VERSION 5.7 ;
  NOWIREEXTENSIONATPIN ON ;
  DIVIDERCHAR "/" ;
  BUSBITCHARS "[]" ;
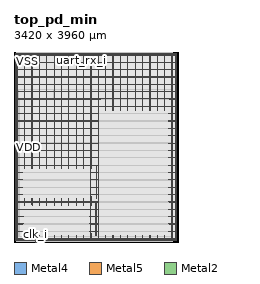
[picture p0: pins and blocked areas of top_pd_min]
MACRO top_pd_min
  CLASS BLOCK ;
  FOREIGN top_pd_min ;
  ORIGIN 0.000 0.000 ;
  SIZE 3420.000 BY 3960.000 ;
  PIN VDD
    DIRECTION INOUT ;
    USE POWER ;
    PORT
      LAYER Metal4 ;
        RECT 42.800 43.360 44.400 3915.840 ;
    END
    PORT
      LAYER Metal4 ;
        RECT 3375.520 43.360 3377.120 3915.840 ;
    END
    PORT
      LAYER Metal5 ;
        RECT 42.800 43.360 3377.120 44.960 ;
    END
    PORT
      LAYER Metal5 ;
        RECT 42.800 3914.240 3377.120 3915.840 ;
    END
    PORT
      LAYER Metal4 ;
        RECT 65.920 40.060 67.520 3919.140 ;
    END
    PORT
      LAYER Metal4 ;
        RECT 219.520 40.060 221.120 139.810 ;
    END
    PORT
      LAYER Metal4 ;
        RECT 219.520 771.220 221.120 909.810 ;
    END
    PORT
      LAYER Metal4 ;
        RECT 219.520 1541.220 221.120 3919.140 ;
    END
    PORT
      LAYER Metal4 ;
        RECT 373.120 40.060 374.720 139.810 ;
    END
    PORT
      LAYER Metal4 ;
        RECT 373.120 771.220 374.720 909.810 ;
    END
    PORT
      LAYER Metal4 ;
        RECT 373.120 1541.220 374.720 3919.140 ;
    END
    PORT
      LAYER Metal4 ;
        RECT 526.720 40.060 528.320 139.810 ;
    END
    PORT
      LAYER Metal4 ;
        RECT 526.720 771.220 528.320 909.810 ;
    END
    PORT
      LAYER Metal4 ;
        RECT 526.720 1541.220 528.320 3919.140 ;
    END
    PORT
      LAYER Metal4 ;
        RECT 680.320 40.060 681.920 139.810 ;
    END
    PORT
      LAYER Metal4 ;
        RECT 680.320 771.220 681.920 909.810 ;
    END
    PORT
      LAYER Metal4 ;
        RECT 680.320 1541.220 681.920 3919.140 ;
    END
    PORT
      LAYER Metal4 ;
        RECT 833.920 40.060 835.520 139.810 ;
    END
    PORT
      LAYER Metal4 ;
        RECT 833.920 771.220 835.520 909.810 ;
    END
    PORT
      LAYER Metal4 ;
        RECT 833.920 1541.220 835.520 3919.140 ;
    END
    PORT
      LAYER Metal4 ;
        RECT 987.520 40.060 989.120 139.810 ;
    END
    PORT
      LAYER Metal4 ;
        RECT 987.520 771.220 989.120 909.810 ;
    END
    PORT
      LAYER Metal4 ;
        RECT 987.520 1541.220 989.120 3919.140 ;
    END
    PORT
      LAYER Metal4 ;
        RECT 1141.120 40.060 1142.720 139.810 ;
    END
    PORT
      LAYER Metal4 ;
        RECT 1141.120 771.220 1142.720 909.810 ;
    END
    PORT
      LAYER Metal4 ;
        RECT 1141.120 1541.220 1142.720 3919.140 ;
    END
    PORT
      LAYER Metal4 ;
        RECT 1294.720 40.060 1296.320 139.810 ;
    END
    PORT
      LAYER Metal4 ;
        RECT 1294.720 771.220 1296.320 909.810 ;
    END
    PORT
      LAYER Metal4 ;
        RECT 1294.720 1541.220 1296.320 3919.140 ;
    END
    PORT
      LAYER Metal4 ;
        RECT 1448.320 40.060 1449.920 139.810 ;
    END
    PORT
      LAYER Metal4 ;
        RECT 1448.320 771.220 1449.920 909.810 ;
    END
    PORT
      LAYER Metal4 ;
        RECT 1448.320 1541.220 1449.920 3919.140 ;
    END
    PORT
      LAYER Metal4 ;
        RECT 1601.920 40.060 1603.520 3919.140 ;
    END
    PORT
      LAYER Metal4 ;
        RECT 1755.520 40.060 1757.120 3919.140 ;
    END
    PORT
      LAYER Metal4 ;
        RECT 1909.120 40.060 1910.720 139.810 ;
    END
    PORT
      LAYER Metal4 ;
        RECT 1909.120 2734.020 1910.720 3919.140 ;
    END
    PORT
      LAYER Metal4 ;
        RECT 2062.720 40.060 2064.320 139.810 ;
    END
    PORT
      LAYER Metal4 ;
        RECT 2062.720 2734.020 2064.320 3919.140 ;
    END
    PORT
      LAYER Metal4 ;
        RECT 2216.320 40.060 2217.920 139.810 ;
    END
    PORT
      LAYER Metal4 ;
        RECT 2216.320 2734.020 2217.920 3919.140 ;
    END
    PORT
      LAYER Metal4 ;
        RECT 2369.920 40.060 2371.520 139.810 ;
    END
    PORT
      LAYER Metal4 ;
        RECT 2369.920 2734.020 2371.520 3919.140 ;
    END
    PORT
      LAYER Metal4 ;
        RECT 2523.520 40.060 2525.120 139.810 ;
    END
    PORT
      LAYER Metal4 ;
        RECT 2523.520 2734.020 2525.120 3919.140 ;
    END
    PORT
      LAYER Metal4 ;
        RECT 2677.120 40.060 2678.720 139.810 ;
    END
    PORT
      LAYER Metal4 ;
        RECT 2677.120 2734.020 2678.720 3919.140 ;
    END
    PORT
      LAYER Metal4 ;
        RECT 2830.720 40.060 2832.320 139.810 ;
    END
    PORT
      LAYER Metal4 ;
        RECT 2830.720 2734.020 2832.320 3919.140 ;
    END
    PORT
      LAYER Metal4 ;
        RECT 2984.320 40.060 2985.920 139.810 ;
    END
    PORT
      LAYER Metal4 ;
        RECT 2984.320 2734.020 2985.920 3919.140 ;
    END
    PORT
      LAYER Metal4 ;
        RECT 3137.920 40.060 3139.520 139.810 ;
    END
    PORT
      LAYER Metal4 ;
        RECT 3137.920 2734.020 3139.520 3919.140 ;
    END
    PORT
      LAYER Metal4 ;
        RECT 3291.520 40.060 3293.120 3919.140 ;
    END
    PORT
      LAYER Metal5 ;
        RECT 39.500 66.810 3380.420 68.410 ;
    END
    PORT
      LAYER Metal5 ;
        RECT 39.500 219.990 178.580 221.590 ;
    END
    PORT
      LAYER Metal5 ;
        RECT 39.500 373.170 178.580 374.770 ;
    END
    PORT
      LAYER Metal5 ;
        RECT 39.500 526.350 178.580 527.950 ;
    END
    PORT
      LAYER Metal5 ;
        RECT 39.500 679.530 178.580 681.130 ;
    END
    PORT
      LAYER Metal5 ;
        RECT 39.500 832.710 1770.800 834.310 ;
    END
    PORT
      LAYER Metal5 ;
        RECT 39.500 985.890 178.580 987.490 ;
    END
    PORT
      LAYER Metal5 ;
        RECT 39.500 1139.070 178.580 1140.670 ;
    END
    PORT
      LAYER Metal5 ;
        RECT 39.500 1292.250 178.580 1293.850 ;
    END
    PORT
      LAYER Metal5 ;
        RECT 39.500 1445.430 178.580 1447.030 ;
    END
    PORT
      LAYER Metal5 ;
        RECT 39.500 1598.610 1770.800 1600.210 ;
    END
    PORT
      LAYER Metal5 ;
        RECT 39.500 1751.790 1770.800 1753.390 ;
    END
    PORT
      LAYER Metal5 ;
        RECT 39.500 1904.970 1770.800 1906.570 ;
    END
    PORT
      LAYER Metal5 ;
        RECT 39.500 2058.150 1770.800 2059.750 ;
    END
    PORT
      LAYER Metal5 ;
        RECT 39.500 2211.330 1770.800 2212.930 ;
    END
    PORT
      LAYER Metal5 ;
        RECT 39.500 2364.510 1770.800 2366.110 ;
    END
    PORT
      LAYER Metal5 ;
        RECT 39.500 2517.690 1770.800 2519.290 ;
    END
    PORT
      LAYER Metal5 ;
        RECT 39.500 2670.870 1770.800 2672.470 ;
    END
    PORT
      LAYER Metal5 ;
        RECT 39.500 2824.050 1798.580 2825.650 ;
    END
    PORT
      LAYER Metal5 ;
        RECT 39.500 2977.230 1798.580 2978.830 ;
    END
    PORT
      LAYER Metal5 ;
        RECT 39.500 3130.410 3380.420 3132.010 ;
    END
    PORT
      LAYER Metal5 ;
        RECT 39.500 3283.590 3380.420 3285.190 ;
    END
    PORT
      LAYER Metal5 ;
        RECT 39.500 3436.770 3380.420 3438.370 ;
    END
    PORT
      LAYER Metal5 ;
        RECT 39.500 3589.950 3380.420 3591.550 ;
    END
    PORT
      LAYER Metal5 ;
        RECT 39.500 3743.130 3380.420 3744.730 ;
    END
    PORT
      LAYER Metal5 ;
        RECT 39.500 3896.310 3380.420 3897.910 ;
    END
    PORT
      LAYER Metal5 ;
        RECT 1621.660 219.990 1770.800 221.590 ;
    END
    PORT
      LAYER Metal5 ;
        RECT 1621.660 373.170 1770.800 374.770 ;
    END
    PORT
      LAYER Metal5 ;
        RECT 1621.660 526.350 1770.800 527.950 ;
    END
    PORT
      LAYER Metal5 ;
        RECT 1621.660 679.530 1770.800 681.130 ;
    END
    PORT
      LAYER Metal5 ;
        RECT 1621.660 985.890 1770.800 987.490 ;
    END
    PORT
      LAYER Metal5 ;
        RECT 1621.660 1139.070 1770.800 1140.670 ;
    END
    PORT
      LAYER Metal5 ;
        RECT 1621.660 1292.250 1770.800 1293.850 ;
    END
    PORT
      LAYER Metal5 ;
        RECT 1621.660 1445.430 1770.800 1447.030 ;
    END
    PORT
      LAYER Metal5 ;
        RECT 3241.660 219.990 3380.420 221.590 ;
    END
    PORT
      LAYER Metal5 ;
        RECT 3241.660 373.170 3380.420 374.770 ;
    END
    PORT
      LAYER Metal5 ;
        RECT 3241.660 526.350 3380.420 527.950 ;
    END
    PORT
      LAYER Metal5 ;
        RECT 3241.660 679.530 3380.420 681.130 ;
    END
    PORT
      LAYER Metal5 ;
        RECT 3241.660 832.710 3380.420 834.310 ;
    END
    PORT
      LAYER Metal5 ;
        RECT 3241.660 985.890 3380.420 987.490 ;
    END
    PORT
      LAYER Metal5 ;
        RECT 3241.660 1139.070 3380.420 1140.670 ;
    END
    PORT
      LAYER Metal5 ;
        RECT 3241.660 1292.250 3380.420 1293.850 ;
    END
    PORT
      LAYER Metal5 ;
        RECT 3241.660 1445.430 3380.420 1447.030 ;
    END
    PORT
      LAYER Metal5 ;
        RECT 3241.660 1598.610 3380.420 1600.210 ;
    END
    PORT
      LAYER Metal5 ;
        RECT 3241.660 1751.790 3380.420 1753.390 ;
    END
    PORT
      LAYER Metal5 ;
        RECT 3241.660 1904.970 3380.420 1906.570 ;
    END
    PORT
      LAYER Metal5 ;
        RECT 3241.660 2058.150 3380.420 2059.750 ;
    END
    PORT
      LAYER Metal5 ;
        RECT 3241.660 2211.330 3380.420 2212.930 ;
    END
    PORT
      LAYER Metal5 ;
        RECT 3241.660 2364.510 3380.420 2366.110 ;
    END
    PORT
      LAYER Metal5 ;
        RECT 3241.660 2517.690 3380.420 2519.290 ;
    END
    PORT
      LAYER Metal5 ;
        RECT 3241.660 2670.870 3380.420 2672.470 ;
    END
    PORT
      LAYER Metal5 ;
        RECT 3241.660 2824.050 3380.420 2825.650 ;
    END
    PORT
      LAYER Metal5 ;
        RECT 3241.660 2977.230 3380.420 2978.830 ;
    END
  END VDD
  PIN VSS
    DIRECTION INOUT ;
    USE GROUND ;
    PORT
      LAYER Metal4 ;
        RECT 39.500 40.060 41.100 3919.140 ;
    END
    PORT
      LAYER Metal4 ;
        RECT 3378.820 40.060 3380.420 3919.140 ;
    END
    PORT
      LAYER Metal5 ;
        RECT 39.500 40.060 3380.420 41.660 ;
    END
    PORT
      LAYER Metal5 ;
        RECT 39.500 3917.540 3380.420 3919.140 ;
    END
    PORT
      LAYER Metal4 ;
        RECT 69.220 40.060 70.820 3919.140 ;
    END
    PORT
      LAYER Metal4 ;
        RECT 222.820 40.060 224.420 139.810 ;
    END
    PORT
      LAYER Metal4 ;
        RECT 222.820 758.830 224.420 909.810 ;
    END
    PORT
      LAYER Metal4 ;
        RECT 222.820 1528.830 224.420 3919.140 ;
    END
    PORT
      LAYER Metal4 ;
        RECT 376.420 40.060 378.020 139.810 ;
    END
    PORT
      LAYER Metal4 ;
        RECT 376.420 758.830 378.020 909.810 ;
    END
    PORT
      LAYER Metal4 ;
        RECT 376.420 1528.830 378.020 3919.140 ;
    END
    PORT
      LAYER Metal4 ;
        RECT 530.020 40.060 531.620 139.810 ;
    END
    PORT
      LAYER Metal4 ;
        RECT 530.020 758.830 531.620 909.810 ;
    END
    PORT
      LAYER Metal4 ;
        RECT 530.020 1528.830 531.620 3919.140 ;
    END
    PORT
      LAYER Metal4 ;
        RECT 683.620 40.060 685.220 139.810 ;
    END
    PORT
      LAYER Metal4 ;
        RECT 683.620 758.830 685.220 909.810 ;
    END
    PORT
      LAYER Metal4 ;
        RECT 683.620 1528.830 685.220 3919.140 ;
    END
    PORT
      LAYER Metal4 ;
        RECT 837.220 40.060 838.820 139.810 ;
    END
    PORT
      LAYER Metal4 ;
        RECT 837.220 758.830 838.820 909.810 ;
    END
    PORT
      LAYER Metal4 ;
        RECT 837.220 1528.830 838.820 3919.140 ;
    END
    PORT
      LAYER Metal4 ;
        RECT 990.820 40.060 992.420 139.810 ;
    END
    PORT
      LAYER Metal4 ;
        RECT 990.820 758.830 992.420 909.810 ;
    END
    PORT
      LAYER Metal4 ;
        RECT 990.820 1528.830 992.420 3919.140 ;
    END
    PORT
      LAYER Metal4 ;
        RECT 1144.420 40.060 1146.020 139.810 ;
    END
    PORT
      LAYER Metal4 ;
        RECT 1144.420 758.830 1146.020 909.810 ;
    END
    PORT
      LAYER Metal4 ;
        RECT 1144.420 1528.830 1146.020 3919.140 ;
    END
    PORT
      LAYER Metal4 ;
        RECT 1298.020 40.060 1299.620 139.810 ;
    END
    PORT
      LAYER Metal4 ;
        RECT 1298.020 758.830 1299.620 909.810 ;
    END
    PORT
      LAYER Metal4 ;
        RECT 1298.020 1528.830 1299.620 3919.140 ;
    END
    PORT
      LAYER Metal4 ;
        RECT 1451.620 40.060 1453.220 139.810 ;
    END
    PORT
      LAYER Metal4 ;
        RECT 1451.620 758.830 1453.220 909.810 ;
    END
    PORT
      LAYER Metal4 ;
        RECT 1451.620 1528.830 1453.220 3919.140 ;
    END
    PORT
      LAYER Metal4 ;
        RECT 1605.220 40.060 1606.820 182.800 ;
    END
    PORT
      LAYER Metal4 ;
        RECT 1605.220 767.920 1606.820 952.800 ;
    END
    PORT
      LAYER Metal4 ;
        RECT 1605.220 1537.920 1606.820 3919.140 ;
    END
    PORT
      LAYER Metal4 ;
        RECT 1758.820 40.060 1760.420 139.810 ;
    END
    PORT
      LAYER Metal4 ;
        RECT 1758.820 2734.020 1760.420 3919.140 ;
    END
    PORT
      LAYER Metal4 ;
        RECT 1912.420 40.060 1914.020 139.810 ;
    END
    PORT
      LAYER Metal4 ;
        RECT 1912.420 2734.020 1914.020 3919.140 ;
    END
    PORT
      LAYER Metal4 ;
        RECT 2066.020 40.060 2067.620 139.810 ;
    END
    PORT
      LAYER Metal4 ;
        RECT 2066.020 2734.020 2067.620 3919.140 ;
    END
    PORT
      LAYER Metal4 ;
        RECT 2219.620 40.060 2221.220 139.810 ;
    END
    PORT
      LAYER Metal4 ;
        RECT 2219.620 2734.020 2221.220 3919.140 ;
    END
    PORT
      LAYER Metal4 ;
        RECT 2373.220 40.060 2374.820 139.810 ;
    END
    PORT
      LAYER Metal4 ;
        RECT 2373.220 2734.020 2374.820 3919.140 ;
    END
    PORT
      LAYER Metal4 ;
        RECT 2526.820 40.060 2528.420 139.810 ;
    END
    PORT
      LAYER Metal4 ;
        RECT 2526.820 2734.020 2528.420 3919.140 ;
    END
    PORT
      LAYER Metal4 ;
        RECT 2680.420 40.060 2682.020 139.810 ;
    END
    PORT
      LAYER Metal4 ;
        RECT 2680.420 2734.020 2682.020 3919.140 ;
    END
    PORT
      LAYER Metal4 ;
        RECT 2834.020 40.060 2835.620 139.810 ;
    END
    PORT
      LAYER Metal4 ;
        RECT 2834.020 2734.020 2835.620 3919.140 ;
    END
    PORT
      LAYER Metal4 ;
        RECT 2987.620 40.060 2989.220 139.810 ;
    END
    PORT
      LAYER Metal4 ;
        RECT 2987.620 2734.020 2989.220 3919.140 ;
    END
    PORT
      LAYER Metal4 ;
        RECT 3141.220 40.060 3142.820 139.810 ;
    END
    PORT
      LAYER Metal4 ;
        RECT 3141.220 2734.020 3142.820 3919.140 ;
    END
    PORT
      LAYER Metal4 ;
        RECT 3294.820 40.060 3296.420 3919.140 ;
    END
    PORT
      LAYER Metal5 ;
        RECT 39.500 70.110 3380.420 71.710 ;
    END
    PORT
      LAYER Metal5 ;
        RECT 39.500 223.290 189.440 224.890 ;
    END
    PORT
      LAYER Metal5 ;
        RECT 39.500 376.470 189.440 378.070 ;
    END
    PORT
      LAYER Metal5 ;
        RECT 39.500 529.650 189.440 531.250 ;
    END
    PORT
      LAYER Metal5 ;
        RECT 39.500 682.830 1770.800 684.430 ;
    END
    PORT
      LAYER Metal5 ;
        RECT 39.500 836.010 1770.800 837.610 ;
    END
    PORT
      LAYER Metal5 ;
        RECT 39.500 989.190 178.580 990.790 ;
    END
    PORT
      LAYER Metal5 ;
        RECT 39.500 1142.370 178.580 1143.970 ;
    END
    PORT
      LAYER Metal5 ;
        RECT 39.500 1295.550 178.580 1297.150 ;
    END
    PORT
      LAYER Metal5 ;
        RECT 39.500 1448.730 178.580 1450.330 ;
    END
    PORT
      LAYER Metal5 ;
        RECT 39.500 1601.910 1770.800 1603.510 ;
    END
    PORT
      LAYER Metal5 ;
        RECT 39.500 1755.090 1770.800 1756.690 ;
    END
    PORT
      LAYER Metal5 ;
        RECT 39.500 1908.270 1770.800 1909.870 ;
    END
    PORT
      LAYER Metal5 ;
        RECT 39.500 2061.450 1770.800 2063.050 ;
    END
    PORT
      LAYER Metal5 ;
        RECT 39.500 2214.630 1770.800 2216.230 ;
    END
    PORT
      LAYER Metal5 ;
        RECT 39.500 2367.810 1770.800 2369.410 ;
    END
    PORT
      LAYER Metal5 ;
        RECT 39.500 2520.990 1770.800 2522.590 ;
    END
    PORT
      LAYER Metal5 ;
        RECT 39.500 2674.170 1770.800 2675.770 ;
    END
    PORT
      LAYER Metal5 ;
        RECT 39.500 2827.350 3380.420 2828.950 ;
    END
    PORT
      LAYER Metal5 ;
        RECT 39.500 2980.530 3380.420 2982.130 ;
    END
    PORT
      LAYER Metal5 ;
        RECT 39.500 3133.710 3380.420 3135.310 ;
    END
    PORT
      LAYER Metal5 ;
        RECT 39.500 3286.890 3380.420 3288.490 ;
    END
    PORT
      LAYER Metal5 ;
        RECT 39.500 3440.070 3380.420 3441.670 ;
    END
    PORT
      LAYER Metal5 ;
        RECT 39.500 3593.250 3380.420 3594.850 ;
    END
    PORT
      LAYER Metal5 ;
        RECT 39.500 3746.430 3380.420 3748.030 ;
    END
    PORT
      LAYER Metal5 ;
        RECT 39.500 3899.610 3380.420 3901.210 ;
    END
    PORT
      LAYER Metal5 ;
        RECT 1579.440 223.290 1770.800 224.890 ;
    END
    PORT
      LAYER Metal5 ;
        RECT 1579.440 376.470 1770.800 378.070 ;
    END
    PORT
      LAYER Metal5 ;
        RECT 1579.440 529.650 1770.800 531.250 ;
    END
    PORT
      LAYER Metal5 ;
        RECT 1621.660 989.190 1770.800 990.790 ;
    END
    PORT
      LAYER Metal5 ;
        RECT 1621.660 1142.370 1770.800 1143.970 ;
    END
    PORT
      LAYER Metal5 ;
        RECT 1621.660 1295.550 1770.800 1297.150 ;
    END
    PORT
      LAYER Metal5 ;
        RECT 1621.660 1448.730 1770.800 1450.330 ;
    END
    PORT
      LAYER Metal5 ;
        RECT 3227.440 223.290 3380.420 224.890 ;
    END
    PORT
      LAYER Metal5 ;
        RECT 3227.440 376.470 3380.420 378.070 ;
    END
    PORT
      LAYER Metal5 ;
        RECT 3227.440 529.650 3380.420 531.250 ;
    END
    PORT
      LAYER Metal5 ;
        RECT 3227.440 682.830 3380.420 684.430 ;
    END
    PORT
      LAYER Metal5 ;
        RECT 3227.440 836.010 3380.420 837.610 ;
    END
    PORT
      LAYER Metal5 ;
        RECT 3227.440 989.190 3380.420 990.790 ;
    END
    PORT
      LAYER Metal5 ;
        RECT 3227.440 1142.370 3380.420 1143.970 ;
    END
    PORT
      LAYER Metal5 ;
        RECT 3227.440 1295.550 3380.420 1297.150 ;
    END
    PORT
      LAYER Metal5 ;
        RECT 3227.440 1448.730 3380.420 1450.330 ;
    END
    PORT
      LAYER Metal5 ;
        RECT 3227.440 1601.910 3380.420 1603.510 ;
    END
    PORT
      LAYER Metal5 ;
        RECT 3227.440 1755.090 3380.420 1756.690 ;
    END
    PORT
      LAYER Metal5 ;
        RECT 3227.440 1908.270 3380.420 1909.870 ;
    END
    PORT
      LAYER Metal5 ;
        RECT 3227.440 2061.450 3380.420 2063.050 ;
    END
    PORT
      LAYER Metal5 ;
        RECT 3227.440 2214.630 3380.420 2216.230 ;
    END
    PORT
      LAYER Metal5 ;
        RECT 3227.440 2367.810 3380.420 2369.410 ;
    END
    PORT
      LAYER Metal5 ;
        RECT 3227.440 2520.990 3380.420 2522.590 ;
    END
    PORT
      LAYER Metal5 ;
        RECT 3227.440 2674.170 3380.420 2675.770 ;
    END
    PORT
      LAYER Metal4 ;
        RECT 1708.600 136.900 1710.200 811.740 ;
    END
    PORT
      LAYER Metal4 ;
        RECT 1709.160 905.220 1710.760 1587.900 ;
    END
  END VSS
  PIN clk_i
    DIRECTION INPUT ;
    USE SIGNAL ;
    ANTENNAGATEAREA 9.476000 ;
    PORT
      LAYER Metal2 ;
        RECT 449.120 0.000 449.680 0.560 ;
    END
  END clk_i
  PIN rst_ni
    DIRECTION INPUT ;
    USE SIGNAL ;
    ANTENNAGATEAREA 0.396000 ;
    PORT
      LAYER Metal2 ;
        RECT 450.240 0.000 450.800 0.560 ;
    END
  END rst_ni
  PIN uart_rx_i
    DIRECTION INPUT ;
    USE SIGNAL ;
    ANTENNAGATEAREA 0.726000 ;
    PORT
      LAYER Metal2 ;
        RECT 1413.440 3959.440 1414.000 3960.000 ;
    END
  END uart_rx_i
  PIN uart_tx_en_o
    DIRECTION OUTPUT ;
    USE SIGNAL ;
    ANTENNADIFFAREA 0.536800 ;
    PORT
      LAYER Metal2 ;
        RECT 324.800 3959.440 325.360 3960.000 ;
    END
  END uart_tx_en_o
  PIN uart_tx_o
    DIRECTION OUTPUT ;
    USE SIGNAL ;
    ANTENNADIFFAREA 0.897600 ;
    PORT
      LAYER Metal2 ;
        RECT 1412.320 3959.440 1412.880 3960.000 ;
    END
  END uart_tx_o
  OBS
      LAYER Nwell ;
        RECT 49.970 50.530 3369.950 3908.670 ;
      LAYER Metal1 ;
        RECT 50.400 50.660 3369.520 3908.540 ;
      LAYER Metal2 ;
        RECT 52.780 3959.140 324.500 3959.440 ;
        RECT 325.660 3959.140 1412.020 3959.440 ;
        RECT 1414.300 3959.140 3296.280 3959.440 ;
        RECT 52.780 0.860 3296.280 3959.140 ;
        RECT 52.780 0.090 448.820 0.860 ;
        RECT 451.100 0.090 3296.280 0.860 ;
      LAYER Metal3 ;
        RECT 52.730 0.140 3296.330 3914.260 ;
      LAYER Metal4 ;
        RECT 84.140 1540.920 219.220 3183.510 ;
        RECT 221.420 1540.920 222.520 3183.510 ;
        RECT 84.140 1528.530 222.520 1540.920 ;
        RECT 224.720 1540.920 372.820 3183.510 ;
        RECT 375.020 1540.920 376.120 3183.510 ;
        RECT 224.720 1528.530 376.120 1540.920 ;
        RECT 378.320 1540.920 526.420 3183.510 ;
        RECT 528.620 1540.920 529.720 3183.510 ;
        RECT 378.320 1528.530 529.720 1540.920 ;
        RECT 531.920 1540.920 680.020 3183.510 ;
        RECT 682.220 1540.920 683.320 3183.510 ;
        RECT 531.920 1528.530 683.320 1540.920 ;
        RECT 685.520 1540.920 833.620 3183.510 ;
        RECT 835.820 1540.920 836.920 3183.510 ;
        RECT 685.520 1528.530 836.920 1540.920 ;
        RECT 839.120 1540.920 987.220 3183.510 ;
        RECT 989.420 1540.920 990.520 3183.510 ;
        RECT 839.120 1528.530 990.520 1540.920 ;
        RECT 992.720 1540.920 1140.820 3183.510 ;
        RECT 1143.020 1540.920 1144.120 3183.510 ;
        RECT 992.720 1528.530 1144.120 1540.920 ;
        RECT 1146.320 1540.920 1294.420 3183.510 ;
        RECT 1296.620 1540.920 1297.720 3183.510 ;
        RECT 1146.320 1528.530 1297.720 1540.920 ;
        RECT 1299.920 1540.920 1448.020 3183.510 ;
        RECT 1450.220 1540.920 1451.320 3183.510 ;
        RECT 1299.920 1528.530 1451.320 1540.920 ;
        RECT 1453.520 1528.530 1601.620 3183.510 ;
        RECT 84.140 910.110 1601.620 1528.530 ;
        RECT 84.140 770.920 219.220 910.110 ;
        RECT 221.420 770.920 222.520 910.110 ;
        RECT 84.140 758.530 222.520 770.920 ;
        RECT 224.720 770.920 372.820 910.110 ;
        RECT 375.020 770.920 376.120 910.110 ;
        RECT 224.720 758.530 376.120 770.920 ;
        RECT 378.320 770.920 526.420 910.110 ;
        RECT 528.620 770.920 529.720 910.110 ;
        RECT 378.320 758.530 529.720 770.920 ;
        RECT 531.920 770.920 680.020 910.110 ;
        RECT 682.220 770.920 683.320 910.110 ;
        RECT 531.920 758.530 683.320 770.920 ;
        RECT 685.520 770.920 833.620 910.110 ;
        RECT 835.820 770.920 836.920 910.110 ;
        RECT 685.520 758.530 836.920 770.920 ;
        RECT 839.120 770.920 987.220 910.110 ;
        RECT 989.420 770.920 990.520 910.110 ;
        RECT 839.120 758.530 990.520 770.920 ;
        RECT 992.720 770.920 1140.820 910.110 ;
        RECT 1143.020 770.920 1144.120 910.110 ;
        RECT 992.720 758.530 1144.120 770.920 ;
        RECT 1146.320 770.920 1294.420 910.110 ;
        RECT 1296.620 770.920 1297.720 910.110 ;
        RECT 1146.320 758.530 1297.720 770.920 ;
        RECT 1299.920 770.920 1448.020 910.110 ;
        RECT 1450.220 770.920 1451.320 910.110 ;
        RECT 1299.920 758.530 1451.320 770.920 ;
        RECT 1453.520 758.530 1601.620 910.110 ;
        RECT 84.140 140.110 1601.620 758.530 ;
        RECT 84.140 114.330 219.220 140.110 ;
        RECT 221.420 114.330 222.520 140.110 ;
        RECT 224.720 114.330 372.820 140.110 ;
        RECT 375.020 114.330 376.120 140.110 ;
        RECT 378.320 114.330 526.420 140.110 ;
        RECT 528.620 114.330 529.720 140.110 ;
        RECT 531.920 114.330 680.020 140.110 ;
        RECT 682.220 114.330 683.320 140.110 ;
        RECT 685.520 114.330 833.620 140.110 ;
        RECT 835.820 114.330 836.920 140.110 ;
        RECT 839.120 114.330 987.220 140.110 ;
        RECT 989.420 114.330 990.520 140.110 ;
        RECT 992.720 114.330 1140.820 140.110 ;
        RECT 1143.020 114.330 1144.120 140.110 ;
        RECT 1146.320 114.330 1294.420 140.110 ;
        RECT 1296.620 114.330 1297.720 140.110 ;
        RECT 1299.920 114.330 1448.020 140.110 ;
        RECT 1450.220 114.330 1451.320 140.110 ;
        RECT 1453.520 114.330 1601.620 140.110 ;
        RECT 1603.820 1537.620 1604.920 3183.510 ;
        RECT 1607.120 1588.200 1755.220 3183.510 ;
        RECT 1607.120 1537.620 1708.860 1588.200 ;
        RECT 1603.820 953.100 1708.860 1537.620 ;
        RECT 1603.820 767.620 1604.920 953.100 ;
        RECT 1607.120 904.920 1708.860 953.100 ;
        RECT 1711.060 904.920 1755.220 1588.200 ;
        RECT 1607.120 812.040 1755.220 904.920 ;
        RECT 1607.120 767.620 1708.300 812.040 ;
        RECT 1603.820 183.100 1708.300 767.620 ;
        RECT 1603.820 114.330 1604.920 183.100 ;
        RECT 1607.120 136.600 1708.300 183.100 ;
        RECT 1710.500 136.600 1755.220 812.040 ;
        RECT 1607.120 114.330 1755.220 136.600 ;
        RECT 1757.420 2733.720 1758.520 3183.510 ;
        RECT 1760.720 2733.720 1908.820 3183.510 ;
        RECT 1911.020 2733.720 1912.120 3183.510 ;
        RECT 1914.320 2733.720 2062.420 3183.510 ;
        RECT 2064.620 2733.720 2065.720 3183.510 ;
        RECT 2067.920 2733.720 2216.020 3183.510 ;
        RECT 2218.220 2733.720 2219.320 3183.510 ;
        RECT 2221.520 2733.720 2369.620 3183.510 ;
        RECT 2371.820 2733.720 2372.920 3183.510 ;
        RECT 2375.120 2733.720 2523.220 3183.510 ;
        RECT 2525.420 2733.720 2526.520 3183.510 ;
        RECT 2528.720 2733.720 2676.820 3183.510 ;
        RECT 2679.020 2733.720 2680.120 3183.510 ;
        RECT 2682.320 2733.720 2830.420 3183.510 ;
        RECT 2832.620 2733.720 2833.720 3183.510 ;
        RECT 2835.920 2733.720 2984.020 3183.510 ;
        RECT 2986.220 2733.720 2987.320 3183.510 ;
        RECT 2989.520 2733.720 3137.620 3183.510 ;
        RECT 3139.820 2733.720 3140.920 3183.510 ;
        RECT 3143.120 2733.720 3289.860 3183.510 ;
        RECT 1757.420 140.110 3289.860 2733.720 ;
        RECT 1757.420 114.330 1758.520 140.110 ;
        RECT 1760.720 114.330 1908.820 140.110 ;
        RECT 1911.020 114.330 1912.120 140.110 ;
        RECT 1914.320 114.330 2062.420 140.110 ;
        RECT 2064.620 114.330 2065.720 140.110 ;
        RECT 2067.920 114.330 2216.020 140.110 ;
        RECT 2218.220 114.330 2219.320 140.110 ;
        RECT 2221.520 114.330 2369.620 140.110 ;
        RECT 2371.820 114.330 2372.920 140.110 ;
        RECT 2375.120 114.330 2523.220 140.110 ;
        RECT 2525.420 114.330 2526.520 140.110 ;
        RECT 2528.720 114.330 2676.820 140.110 ;
        RECT 2679.020 114.330 2680.120 140.110 ;
        RECT 2682.320 114.330 2830.420 140.110 ;
        RECT 2832.620 114.330 2833.720 140.110 ;
        RECT 2835.920 114.330 2984.020 140.110 ;
        RECT 2986.220 114.330 2987.320 140.110 ;
        RECT 2989.520 114.330 3137.620 140.110 ;
        RECT 3139.820 114.330 3140.920 140.110 ;
        RECT 3143.120 114.330 3289.860 140.110 ;
      LAYER Metal5 ;
        RECT 117.100 2982.730 3289.940 2998.980 ;
        RECT 117.100 2979.430 3289.940 2979.930 ;
        RECT 1799.180 2976.630 3241.060 2979.430 ;
        RECT 117.100 2829.550 3289.940 2976.630 ;
        RECT 117.100 2826.250 3289.940 2826.750 ;
        RECT 1799.180 2823.450 3241.060 2826.250 ;
        RECT 117.100 2676.370 3289.940 2823.450 ;
        RECT 1771.400 2673.570 3226.840 2676.370 ;
        RECT 117.100 2673.070 3289.940 2673.570 ;
        RECT 1771.400 2670.270 3241.060 2673.070 ;
        RECT 117.100 2523.190 3289.940 2670.270 ;
        RECT 1771.400 2520.390 3226.840 2523.190 ;
        RECT 117.100 2519.890 3289.940 2520.390 ;
        RECT 1771.400 2517.090 3241.060 2519.890 ;
        RECT 117.100 2370.010 3289.940 2517.090 ;
        RECT 1771.400 2367.210 3226.840 2370.010 ;
        RECT 117.100 2366.710 3289.940 2367.210 ;
        RECT 1771.400 2363.910 3241.060 2366.710 ;
        RECT 117.100 2216.830 3289.940 2363.910 ;
        RECT 1771.400 2214.030 3226.840 2216.830 ;
        RECT 117.100 2213.530 3289.940 2214.030 ;
        RECT 1771.400 2210.730 3241.060 2213.530 ;
        RECT 117.100 2063.650 3289.940 2210.730 ;
        RECT 1771.400 2060.850 3226.840 2063.650 ;
        RECT 117.100 2060.350 3289.940 2060.850 ;
        RECT 1771.400 2057.550 3241.060 2060.350 ;
        RECT 117.100 1910.470 3289.940 2057.550 ;
        RECT 1771.400 1907.670 3226.840 1910.470 ;
        RECT 117.100 1907.170 3289.940 1907.670 ;
        RECT 1771.400 1904.370 3241.060 1907.170 ;
        RECT 117.100 1757.290 3289.940 1904.370 ;
        RECT 1771.400 1754.490 3226.840 1757.290 ;
        RECT 117.100 1753.990 3289.940 1754.490 ;
        RECT 1771.400 1751.190 3241.060 1753.990 ;
        RECT 117.100 1604.110 3289.940 1751.190 ;
        RECT 1771.400 1601.310 3226.840 1604.110 ;
        RECT 117.100 1600.810 3289.940 1601.310 ;
        RECT 1771.400 1598.010 3241.060 1600.810 ;
        RECT 117.100 1450.930 3289.940 1598.010 ;
        RECT 179.180 1448.130 1621.060 1450.930 ;
        RECT 1771.400 1448.130 3226.840 1450.930 ;
        RECT 117.100 1447.630 3289.940 1448.130 ;
        RECT 179.180 1444.830 1621.060 1447.630 ;
        RECT 1771.400 1444.830 3241.060 1447.630 ;
        RECT 117.100 1297.750 3289.940 1444.830 ;
        RECT 179.180 1294.950 1621.060 1297.750 ;
        RECT 1771.400 1294.950 3226.840 1297.750 ;
        RECT 117.100 1294.450 3289.940 1294.950 ;
        RECT 179.180 1291.650 1621.060 1294.450 ;
        RECT 1771.400 1291.650 3241.060 1294.450 ;
        RECT 117.100 1144.570 3289.940 1291.650 ;
        RECT 179.180 1141.770 1621.060 1144.570 ;
        RECT 1771.400 1141.770 3226.840 1144.570 ;
        RECT 117.100 1141.270 3289.940 1141.770 ;
        RECT 179.180 1138.470 1621.060 1141.270 ;
        RECT 1771.400 1138.470 3241.060 1141.270 ;
        RECT 117.100 991.390 3289.940 1138.470 ;
        RECT 179.180 988.590 1621.060 991.390 ;
        RECT 1771.400 988.590 3226.840 991.390 ;
        RECT 117.100 988.090 3289.940 988.590 ;
        RECT 179.180 985.290 1621.060 988.090 ;
        RECT 1771.400 985.290 3241.060 988.090 ;
        RECT 117.100 838.210 3289.940 985.290 ;
        RECT 1771.400 835.410 3226.840 838.210 ;
        RECT 117.100 834.910 3289.940 835.410 ;
        RECT 1771.400 832.110 3241.060 834.910 ;
        RECT 117.100 685.030 3289.940 832.110 ;
        RECT 1771.400 682.230 3226.840 685.030 ;
        RECT 117.100 681.730 3289.940 682.230 ;
        RECT 179.180 678.930 1621.060 681.730 ;
        RECT 1771.400 678.930 3241.060 681.730 ;
        RECT 117.100 531.850 3289.940 678.930 ;
        RECT 190.040 529.050 1578.840 531.850 ;
        RECT 1771.400 529.050 3226.840 531.850 ;
        RECT 117.100 528.550 3289.940 529.050 ;
        RECT 179.180 525.750 1621.060 528.550 ;
        RECT 1771.400 525.750 3241.060 528.550 ;
        RECT 117.100 378.670 3289.940 525.750 ;
        RECT 190.040 375.870 1578.840 378.670 ;
        RECT 1771.400 375.870 3226.840 378.670 ;
        RECT 117.100 375.370 3289.940 375.870 ;
        RECT 179.180 372.570 1621.060 375.370 ;
        RECT 1771.400 372.570 3241.060 375.370 ;
        RECT 117.100 225.490 3289.940 372.570 ;
        RECT 190.040 222.690 1578.840 225.490 ;
        RECT 1771.400 222.690 3226.840 225.490 ;
        RECT 117.100 222.190 3289.940 222.690 ;
        RECT 179.180 219.390 1621.060 222.190 ;
        RECT 1771.400 219.390 3241.060 222.190 ;
        RECT 117.100 117.230 3289.940 219.390 ;
  END
END top_pd_min
END LIBRARY

